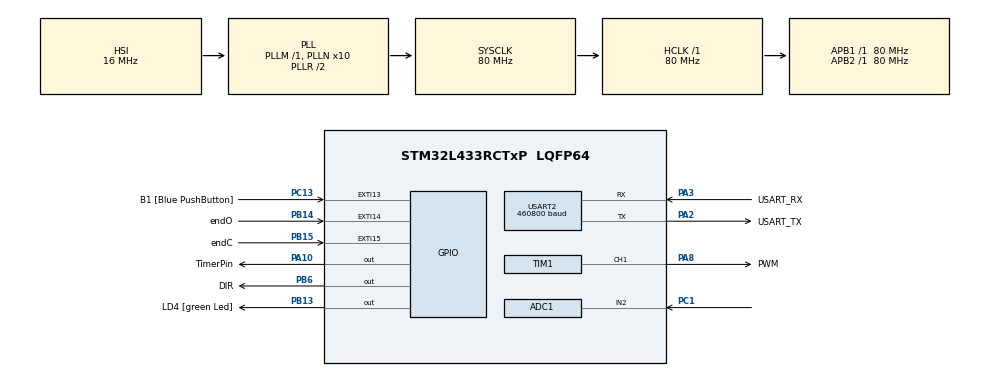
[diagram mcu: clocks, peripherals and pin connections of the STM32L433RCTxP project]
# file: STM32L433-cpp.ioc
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ADC1.Channel-2\#ChannelRegularConversion=ADC_CHANNEL_2
ADC1.NbrOfConversion=1
ADC1.NbrOfConversionFlag=1
ADC1.OffsetNumber-2\#ChannelRegularConversion=ADC_OFFSET_NONE
ADC1.OversamplingMode=ENABLE
ADC1.Rank-2\#ChannelRegularConversion=1
ADC1.Ratio=ADC_OVERSAMPLING_RATIO_4
ADC1.RightBitShift=ADC_RIGHTBITSHIFT_2
ADC1.SamplingTime-2\#ChannelRegularConversion=ADC_SAMPLETIME_12CYCLES_5
ADC1.master=1
Dma.Request0=USART2_RX
Dma.Request1=USART2_TX
Dma.USART2_RX.0.Direction=DMA_PERIPH_TO_MEMORY
Dma.USART2_RX.0.Instance=DMA1_Channel6
Dma.USART2_RX.0.MemDataAlignment=DMA_MDATAALIGN_BYTE
Dma.USART2_RX.0.MemInc=DMA_MINC_ENABLE
Dma.USART2_RX.0.Mode=DMA_NORMAL
Dma.USART2_RX.0.PeriphDataAlignment=DMA_PDATAALIGN_BYTE
Dma.USART2_RX.0.PeriphInc=DMA_PINC_DISABLE
Dma.USART2_RX.0.Priority=DMA_PRIORITY_LOW
Dma.USART2_TX.1.Direction=DMA_MEMORY_TO_PERIPH
Dma.USART2_TX.1.Instance=DMA1_Channel7
Dma.USART2_TX.1.MemDataAlignment=DMA_MDATAALIGN_BYTE
Dma.USART2_TX.1.MemInc=DMA_MINC_ENABLE
Dma.USART2_TX.1.Mode=DMA_NORMAL
Dma.USART2_TX.1.PeriphDataAlignment=DMA_PDATAALIGN_BYTE
Dma.USART2_TX.1.PeriphInc=DMA_PINC_DISABLE
Dma.USART2_TX.1.Priority=DMA_PRIORITY_LOW
Mcu.Family=STM32L4
Mcu.Name=STM32L433RCTxP
Mcu.Package=LQFP64
NVIC.ADC1_IRQn=true\:0\:0\:false\:false\:true\:true\:true\:true
NVIC.DMA1_Channel6_IRQn=true\:0\:0\:false\:false\:true\:false\:true\:true
NVIC.DMA1_Channel7_IRQn=true\:0\:0\:false\:false\:true\:false\:true\:true
NVIC.EXTI15_10_IRQn=true\:0\:0\:false\:false\:true\:true\:true\:true
NVIC.PriorityGroup=NVIC_PRIORITYGROUP_4
NVIC.TIM2_IRQn=true\:0\:0\:false\:false\:true\:true\:true\:true
NVIC.USART2_IRQn=true\:0\:0\:false\:false\:true\:true\:true\:true
PA10.GPIO_Label=TimerPin
PA10.Signal=GPIO_Output
PA13\ (JTMS-SWDIO).GPIO_Label=TMS
PA13\ (JTMS-SWDIO).Mode=Serial_Wire
PA13\ (JTMS-SWDIO).Signal=SYS_JTMS-SWDIO
PA14\ (JTCK-SWCLK).GPIO_Label=TCK
PA14\ (JTCK-SWCLK).Mode=Serial_Wire
PA14\ (JTCK-SWCLK).Signal=SYS_JTCK-SWCLK
PA2.GPIO_Label=USART_TX
PA2.GPIO_Mode=GPIO_MODE_AF_PP
PA2.GPIO_PuPd=GPIO_NOPULL
PA2.GPIO_Speed=GPIO_SPEED_FREQ_VERY_HIGH
PA2.Mode=Asynchronous
PA2.Signal=USART2_TX
PA3.GPIO_Label=USART_RX
PA3.GPIO_Mode=GPIO_MODE_AF_PP
PA3.GPIO_PuPd=GPIO_NOPULL
PA3.GPIO_Speed=GPIO_SPEED_FREQ_VERY_HIGH
PA3.Mode=Asynchronous
PA3.Signal=USART2_RX
PA8.GPIO_Label=PWM
PA8.Signal=S_TIM1_CH1
PB13.GPIO_Label=LD4 [green Led]
PB13.Signal=GPIO_Output
PB14.GPIO_Label=endO
PB14.GPIO_ModeDefaultEXTI=GPIO_MODE_IT_FALLING
PB14.GPIO_PuPd=GPIO_PULLUP
PB14.Signal=GPXTI14
PB15.GPIO_Label=endC
PB15.GPIO_ModeDefaultEXTI=GPIO_MODE_IT_FALLING
PB15.GPIO_PuPd=GPIO_PULLUP
PB15.Signal=GPXTI15
PB3\ (JTDO-TRACESWO).GPIO_Label=SWO
PB3\ (JTDO-TRACESWO).Signal=SYS_JTDO-SWO
PB6.GPIO_Label=DIR
PB6.GPIO_Speed=GPIO_SPEED_FREQ_LOW
PB6.Signal=GPIO_Output
PC1.Signal=ADCx_IN2
PC13.GPIO_Label=B1 [Blue PushButton]
PC13.GPIO_ModeDefaultEXTI=GPIO_MODE_IT_FALLING
PC13.GPIO_PuPd=GPIO_NOPULL
PC13.Signal=GPXTI13
PC14-OSC32_IN\ (PC14).Mode=LSE-External-Oscillator
PC14-OSC32_IN\ (PC14).Signal=RCC_OSC32_IN
PC15-OSC32_OUT\ (PC15).Mode=LSE-External-Oscillator
PC15-OSC32_OUT\ (PC15).Signal=RCC_OSC32_OUT
PH0-OSC_IN\ (PH0).GPIO_Label=MCO
PH0-OSC_IN\ (PH0).Mode=HSE-External-Clock-Source
PH0-OSC_IN\ (PH0).Signal=RCC_OSC_IN
PH1-OSC_OUT\ (PH1).Signal=RCC_OSC_OUT
ProjectManager.HeapSize=0x200
ProjectManager.StackSize=0x400
ProjectManager.TargetToolchain=STM32CubeIDE
RCC.ADCFreq_Value=64000000
RCC.AHBFreq_Value=80000000
RCC.APB1Freq_Value=80000000
RCC.APB1TimFreq_Value=80000000
RCC.APB2Freq_Value=80000000
RCC.APB2TimFreq_Value=80000000
RCC.CortexFreq_Value=80000000
RCC.HCLKFreq_Value=80000000
RCC.HSE_VALUE=8000000
RCC.HSI48_VALUE=48000000
RCC.HSI_VALUE=16000000
RCC.MSI_VALUE=4000000
RCC.PLLN=10
RCC.PLLSourceVirtual=RCC_PLLSOURCE_HSI
RCC.PREFETCH_ENABLE=1
RCC.SYSCLKFreq_VALUE=80000000
RCC.SYSCLKSource=RCC_SYSCLKSOURCE_PLLCLK
RCC.USBFreq_Value=64000000
RCC.VCOOutputFreq_Value=160000000
SH.ADCx_IN2.0=ADC1_IN2,IN2-Single-Ended
SH.S_TIM1_CH1.0=TIM1_CH1,PWM Generation1 CH1
TIM1.Channel-PWM\ Generation1\ CH1=TIM_CHANNEL_1
TIM1.Period=1000-1
TIM1.Prescaler=8-1
TIM1.Pulse-PWM\ Generation1\ CH1=250
TIM2.Period=1000-1
TIM2.Prescaler=80-1
USART2.BaudRate=460800
USART2.VirtualMode-Asynchronous=VM_ASYNC
VP_TIM1_VS_ClockSourceINT.Mode=Internal
VP_TIM2_VS_ClockSourceINT.Mode=Internal
board=NUCLEO-L433RC-P

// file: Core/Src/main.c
/* USER CODE BEGIN Header */
/**
  ******************************************************************************
  * @file           : main.c
  * @brief          : Main program body
  ******************************************************************************
  * @attention
  *
  * Copyright (c) 2022 STMicroelectronics.
  * All rights reserved.
  *
  * This software is licensed under terms that can be found in the LICENSE file
  * in the root directory of this software component.
  * If no LICENSE file comes with this software, it is provided AS-IS.
  *
  ******************************************************************************
  */
/* USER CODE END Header */
#include "main.h"

/* USER CODE BEGIN Includes */
#include "Application.hpp"
#include "Pinout.hpp"
#include "Uart.hpp"
#include"PWM.hpp"
#include "MD10C.hpp"
#include <array>
#include <span>
/* USER CODE END Includes */

ADC_HandleTypeDef hadc1;

TIM_HandleTypeDef htim1;
TIM_HandleTypeDef htim2;

UART_HandleTypeDef huart2;

/* USER CODE BEGIN PV */
/*
Pinout pinout;
Uart uart {huart2};
Adc adc {hadc1};
PWM pwm1 {htim1, TIM1, TIM_CHANNEL_1};
MD10C motor {pinout.m_dir, pwm1};
*/
Application&  application {Application::getInstance(&huart2, &hadc1, &htim1)};
/* USER CODE END PV */

void SystemClock_Config(void);
static void MX_GPIO_Init(void);
static void MX_USART2_UART_Init(void);
static void MX_ADC1_Init(void);
static void MX_TIM2_Init(void);
static void MX_TIM1_Init(void);

int main(void)
{

  /* MCU Configuration--------------------------------------------------------*/

  /* Reset of all peripherals, Initializes the Flash interface and the Systick. */
  HAL_Init();

  /* Configure the system clock */
  SystemClock_Config();

  /* Initialize all configured peripherals */
  MX_GPIO_Init();
  MX_USART2_UART_Init();
  MX_ADC1_Init();
  MX_TIM2_Init();
  MX_TIM1_Init();
  /* USER CODE BEGIN 2 */

  //HAL_TIM_PWM_Start(&htim1, TIM_CHANNEL_1);
  //TIM1->CCR1 = 555;
  //Uart<huart2> uart;  broken
  //std::array<uint8_t, 3> msg {'G', 'O', 'D'};
  //std::array<double, 4> msg1 {1.0,2.5,3.4,4.3};
  //uart.send(std::as_bytes(std::span{msg}));
  /* USER CODE END 2 */

  /* Infinite loop */
  while (1)
  {

  }
}

void SystemClock_Config(void)
{
  RCC_OscInitTypeDef RCC_OscInitStruct = {0};
  RCC_ClkInitTypeDef RCC_ClkInitStruct = {0};

  /** Configure the main internal regulator output voltage
  */
  if (HAL_PWREx_ControlVoltageScaling(PWR_REGULATOR_VOLTAGE_SCALE1) != HAL_OK)
  {
    Error_Handler();
  }

  /** Initializes the RCC Oscillators according to the specified parameters
  * in the RCC_OscInitTypeDef structure.
  */
  RCC_OscInitStruct.OscillatorType = RCC_OSCILLATORTYPE_HSI;
  RCC_OscInitStruct.HSIState = RCC_HSI_ON;
  RCC_OscInitStruct.HSICalibrationValue = RCC_HSICALIBRATION_DEFAULT;
  RCC_OscInitStruct.PLL.PLLState = RCC_PLL_ON;
  RCC_OscInitStruct.PLL.PLLSource = RCC_PLLSOURCE_HSI;
  RCC_OscInitStruct.PLL.PLLM = 1;
  RCC_OscInitStruct.PLL.PLLN = 10;
  RCC_OscInitStruct.PLL.PLLP = RCC_PLLP_DIV7;
  RCC_OscInitStruct.PLL.PLLQ = RCC_PLLQ_DIV2;
  RCC_OscInitStruct.PLL.PLLR = RCC_PLLR_DIV2;
  if (HAL_RCC_OscConfig(&RCC_OscInitStruct) != HAL_OK)
  {
    Error_Handler();
  }

  /** Initializes the CPU, AHB and APB buses clocks
  */
  RCC_ClkInitStruct.ClockType = RCC_CLOCKTYPE_HCLK|RCC_CLOCKTYPE_SYSCLK
                              |RCC_CLOCKTYPE_PCLK1|RCC_CLOCKTYPE_PCLK2;
  RCC_ClkInitStruct.SYSCLKSource = RCC_SYSCLKSOURCE_PLLCLK;
  RCC_ClkInitStruct.AHBCLKDivider = RCC_SYSCLK_DIV1;
  RCC_ClkInitStruct.APB1CLKDivider = RCC_HCLK_DIV1;
  RCC_ClkInitStruct.APB2CLKDivider = RCC_HCLK_DIV1;

  if (HAL_RCC_ClockConfig(&RCC_ClkInitStruct, FLASH_LATENCY_4) != HAL_OK)
  {
    Error_Handler();
  }
}

static void MX_ADC1_Init(void)
{

  ADC_ChannelConfTypeDef sConfig = {0};

  /** Common config
  */
  hadc1.Instance = ADC1;
  hadc1.Init.ClockPrescaler = ADC_CLOCK_ASYNC_DIV1;
  hadc1.Init.Resolution = ADC_RESOLUTION_12B;
  hadc1.Init.DataAlign = ADC_DATAALIGN_RIGHT;
  hadc1.Init.ScanConvMode = ADC_SCAN_DISABLE;
  hadc1.Init.EOCSelection = ADC_EOC_SINGLE_CONV;
  hadc1.Init.LowPowerAutoWait = DISABLE;
  hadc1.Init.ContinuousConvMode = DISABLE;
  hadc1.Init.NbrOfConversion = 1;
  hadc1.Init.DiscontinuousConvMode = DISABLE;
  hadc1.Init.ExternalTrigConv = ADC_SOFTWARE_START;
  hadc1.Init.ExternalTrigConvEdge = ADC_EXTERNALTRIGCONVEDGE_NONE;
  hadc1.Init.DMAContinuousRequests = DISABLE;
  hadc1.Init.Overrun = ADC_OVR_DATA_PRESERVED;
  hadc1.Init.OversamplingMode = ENABLE;
  hadc1.Init.Oversampling.Ratio = ADC_OVERSAMPLING_RATIO_4;
  hadc1.Init.Oversampling.RightBitShift = ADC_RIGHTBITSHIFT_2;
  hadc1.Init.Oversampling.TriggeredMode = ADC_TRIGGEREDMODE_SINGLE_TRIGGER;
  hadc1.Init.Oversampling.OversamplingStopReset = ADC_REGOVERSAMPLING_CONTINUED_MODE;
  if (HAL_ADC_Init(&hadc1) != HAL_OK)
  {
    Error_Handler();
  }

  /** Configure Regular Channel
  */
  sConfig.Channel = ADC_CHANNEL_2;
  sConfig.Rank = ADC_REGULAR_RANK_1;
  sConfig.SamplingTime = ADC_SAMPLETIME_12CYCLES_5;
  sConfig.SingleDiff = ADC_SINGLE_ENDED;
  sConfig.OffsetNumber = ADC_OFFSET_NONE;
  sConfig.Offset = 0;
  if (HAL_ADC_ConfigChannel(&hadc1, &sConfig) != HAL_OK)
  {
    Error_Handler();
  }
  /* USER CODE BEGIN ADC1_Init 2 */
  HAL_ADCEx_Calibration_Start(&hadc1, ADC_SINGLE_ENDED);
  /* USER CODE END ADC1_Init 2 */

}

static void MX_TIM1_Init(void)
{

  TIM_ClockConfigTypeDef sClockSourceConfig = {0};
  TIM_MasterConfigTypeDef sMasterConfig = {0};
  TIM_OC_InitTypeDef sConfigOC = {0};
  TIM_BreakDeadTimeConfigTypeDef sBreakDeadTimeConfig = {0};

  htim1.Instance = TIM1;
  htim1.Init.Prescaler = 8-1;
  htim1.Init.CounterMode = TIM_COUNTERMODE_UP;
  htim1.Init.Period = 1000-1;
  htim1.Init.ClockDivision = TIM_CLOCKDIVISION_DIV1;
  htim1.Init.RepetitionCounter = 0;
  htim1.Init.AutoReloadPreload = TIM_AUTORELOAD_PRELOAD_DISABLE;
  if (HAL_TIM_Base_Init(&htim1) != HAL_OK)
  {
    Error_Handler();
  }
  sClockSourceConfig.ClockSource = TIM_CLOCKSOURCE_INTERNAL;
  if (HAL_TIM_ConfigClockSource(&htim1, &sClockSourceConfig) != HAL_OK)
  {
    Error_Handler();
  }
  if (HAL_TIM_PWM_Init(&htim1) != HAL_OK)
  {
    Error_Handler();
  }
  sMasterConfig.MasterOutputTrigger = TIM_TRGO_RESET;
  sMasterConfig.MasterOutputTrigger2 = TIM_TRGO2_RESET;
  sMasterConfig.MasterSlaveMode = TIM_MASTERSLAVEMODE_DISABLE;
  if (HAL_TIMEx_MasterConfigSynchronization(&htim1, &sMasterConfig) != HAL_OK)
  {
    Error_Handler();
  }
  sConfigOC.OCMode = TIM_OCMODE_PWM1;
  sConfigOC.Pulse = 250;
  sConfigOC.OCPolarity = TIM_OCPOLARITY_HIGH;
  sConfigOC.OCNPolarity = TIM_OCNPOLARITY_HIGH;
  sConfigOC.OCFastMode = TIM_OCFAST_DISABLE;
  sConfigOC.OCIdleState = TIM_OCIDLESTATE_RESET;
  sConfigOC.OCNIdleState = TIM_OCNIDLESTATE_RESET;
  if (HAL_TIM_PWM_ConfigChannel(&htim1, &sConfigOC, TIM_CHANNEL_1) != HAL_OK)
  {
    Error_Handler();
  }
  sBreakDeadTimeConfig.OffStateRunMode = TIM_OSSR_DISABLE;
  sBreakDeadTimeConfig.OffStateIDLEMode = TIM_OSSI_DISABLE;
  sBreakDeadTimeConfig.LockLevel = TIM_LOCKLEVEL_OFF;
  sBreakDeadTimeConfig.DeadTime = 0;
  sBreakDeadTimeConfig.BreakState = TIM_BREAK_DISABLE;
  sBreakDeadTimeConfig.BreakPolarity = TIM_BREAKPOLARITY_HIGH;
  sBreakDeadTimeConfig.BreakFilter = 0;
  sBreakDeadTimeConfig.Break2State = TIM_BREAK2_DISABLE;
  sBreakDeadTimeConfig.Break2Polarity = TIM_BREAK2POLARITY_HIGH;
  sBreakDeadTimeConfig.Break2Filter = 0;
  sBreakDeadTimeConfig.AutomaticOutput = TIM_AUTOMATICOUTPUT_DISABLE;
  if (HAL_TIMEx_ConfigBreakDeadTime(&htim1, &sBreakDeadTimeConfig) != HAL_OK)
  {
    Error_Handler();
  }
  HAL_TIM_MspPostInit(&htim1);

}

static void MX_TIM2_Init(void)
{

  TIM_ClockConfigTypeDef sClockSourceConfig = {0};
  TIM_MasterConfigTypeDef sMasterConfig = {0};

  htim2.Instance = TIM2;
  htim2.Init.Prescaler = 80;
  htim2.Init.CounterMode = TIM_COUNTERMODE_UP;
  htim2.Init.Period = 4294967295;
  htim2.Init.ClockDivision = TIM_CLOCKDIVISION_DIV1;
  htim2.Init.AutoReloadPreload = TIM_AUTORELOAD_PRELOAD_DISABLE;
  if (HAL_TIM_Base_Init(&htim2) != HAL_OK)
  {
    Error_Handler();
  }
  sClockSourceConfig.ClockSource = TIM_CLOCKSOURCE_INTERNAL;
  if (HAL_TIM_ConfigClockSource(&htim2, &sClockSourceConfig) != HAL_OK)
  {
    Error_Handler();
  }
  sMasterConfig.MasterOutputTrigger = TIM_TRGO_RESET;
  sMasterConfig.MasterSlaveMode = TIM_MASTERSLAVEMODE_DISABLE;
  if (HAL_TIMEx_MasterConfigSynchronization(&htim2, &sMasterConfig) != HAL_OK)
  {
    Error_Handler();
  }

}

static void MX_USART2_UART_Init(void)
{

  huart2.Instance = USART2;
  huart2.Init.BaudRate = 115200;
  huart2.Init.WordLength = UART_WORDLENGTH_8B;
  huart2.Init.StopBits = UART_STOPBITS_1;
  huart2.Init.Parity = UART_PARITY_NONE;
  huart2.Init.Mode = UART_MODE_TX_RX;
  huart2.Init.HwFlowCtl = UART_HWCONTROL_NONE;
  huart2.Init.OverSampling = UART_OVERSAMPLING_16;
  huart2.Init.OneBitSampling = UART_ONE_BIT_SAMPLE_DISABLE;
  huart2.AdvancedInit.AdvFeatureInit = UART_ADVFEATURE_NO_INIT;
  if (HAL_UART_Init(&huart2) != HAL_OK)
  {
    Error_Handler();
  }

}

static void MX_GPIO_Init(void)
{
  GPIO_InitTypeDef GPIO_InitStruct = {0};

  /* GPIO Ports Clock Enable */
  __HAL_RCC_GPIOC_CLK_ENABLE();
  __HAL_RCC_GPIOH_CLK_ENABLE();
  __HAL_RCC_GPIOA_CLK_ENABLE();
  __HAL_RCC_GPIOB_CLK_ENABLE();

  /*Configure GPIO pin Output Level */
  HAL_GPIO_WritePin(GPIOA, SMPS_EN_Pin|SMPS_V1_Pin, GPIO_PIN_RESET);

  /*Configure GPIO pin Output Level */
  HAL_GPIO_WritePin(GPIOB, LD4_Pin|DIR_Pin, GPIO_PIN_RESET);

  /*Configure GPIO pin : B1_Pin */
  GPIO_InitStruct.Pin = B1_Pin;
  GPIO_InitStruct.Mode = GPIO_MODE_IT_FALLING;
  GPIO_InitStruct.Pull = GPIO_NOPULL;
  HAL_GPIO_Init(B1_GPIO_Port, &GPIO_InitStruct);

  /*Configure GPIO pins : SMPS_EN_Pin SMPS_V1_Pin */
  GPIO_InitStruct.Pin = SMPS_EN_Pin|SMPS_V1_Pin;
  GPIO_InitStruct.Mode = GPIO_MODE_OUTPUT_PP;
  GPIO_InitStruct.Pull = GPIO_NOPULL;
  GPIO_InitStruct.Speed = GPIO_SPEED_FREQ_LOW;
  HAL_GPIO_Init(GPIOA, &GPIO_InitStruct);

  /*Configure GPIO pin : SMPS_PG_Pin */
  GPIO_InitStruct.Pin = SMPS_PG_Pin;
  GPIO_InitStruct.Mode = GPIO_MODE_INPUT;
  GPIO_InitStruct.Pull = GPIO_PULLUP;
  HAL_GPIO_Init(SMPS_PG_GPIO_Port, &GPIO_InitStruct);

  /*Configure GPIO pins : LD4_Pin DIR_Pin */
  GPIO_InitStruct.Pin = LD4_Pin|DIR_Pin;
  GPIO_InitStruct.Mode = GPIO_MODE_OUTPUT_PP;
  GPIO_InitStruct.Pull = GPIO_NOPULL;
  GPIO_InitStruct.Speed = GPIO_SPEED_FREQ_LOW;
  HAL_GPIO_Init(GPIOB, &GPIO_InitStruct);

}

void Error_Handler(void)
{
  __disable_irq();
  while (1)
  {
  }
}
